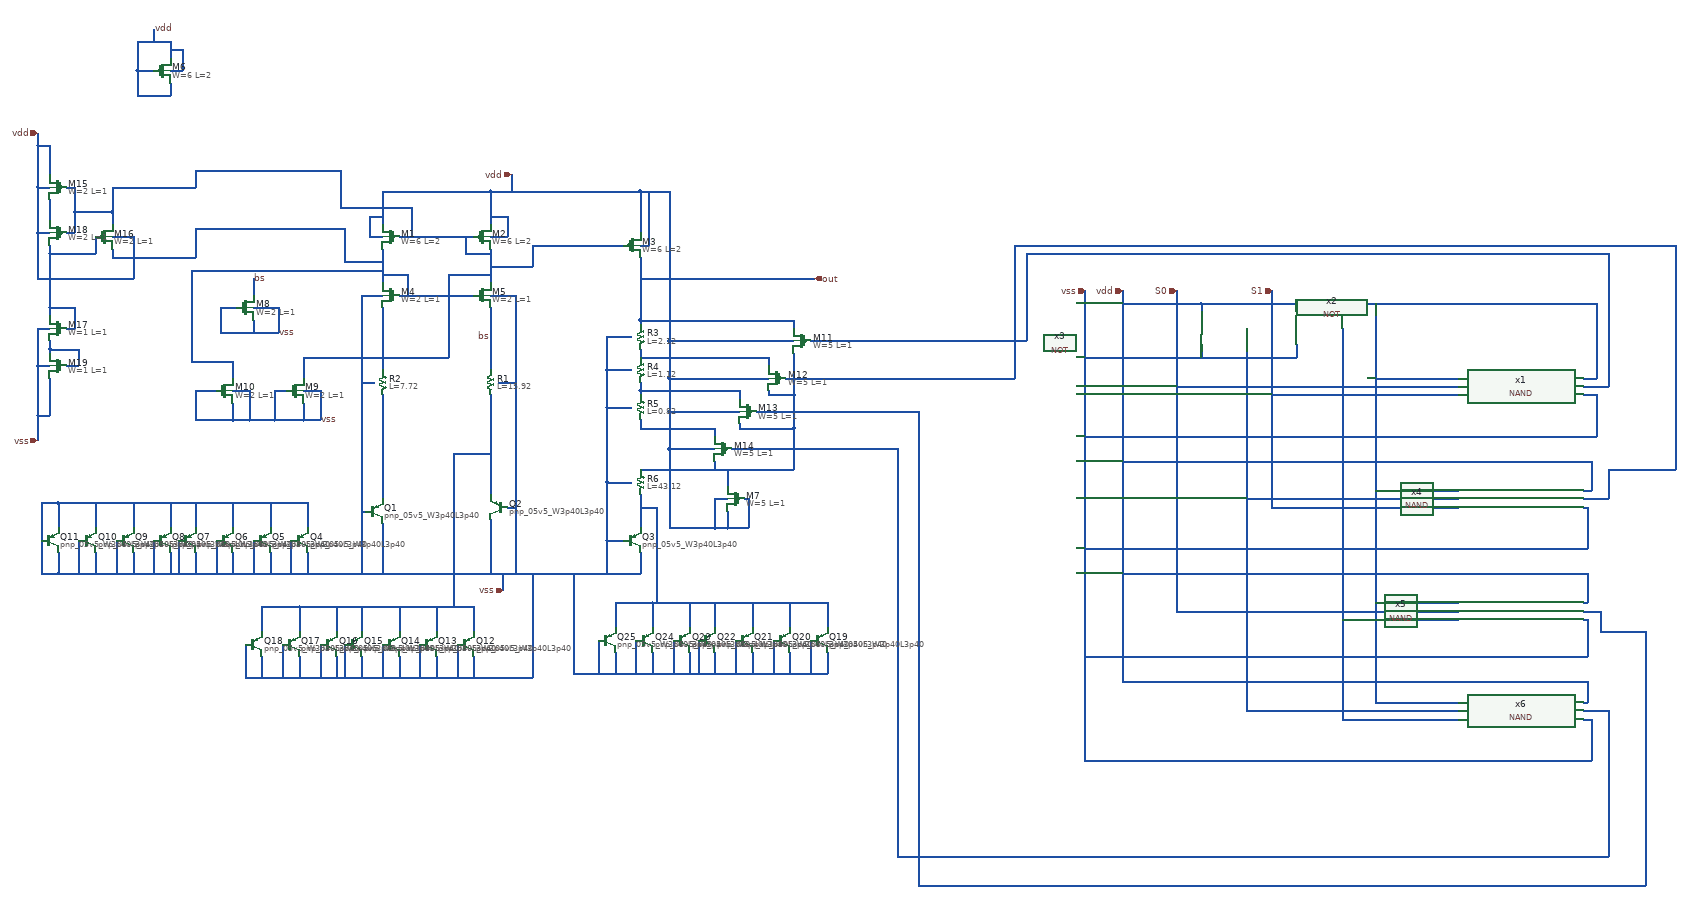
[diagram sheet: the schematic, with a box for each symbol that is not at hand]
v {xschem version=3.4.8RC file_version=1.3}
G {}
K {}
V {}
S {}
F {}
E {}
P 4 1 -840 -730 {}
N 230 -160 230 -110 {lab=#net1}
N 150 -190 210 -190 {lab=vss}
N 150 -190 150 -80 {lab=vss}
N 230 -340 230 -320 {lab=#net2}
N 150 -370 150 -190 {lab=vss}
N 150 -460 210 -460 {lab=vss}
N 150 -370 210 -370 {lab=vss}
N 230 -580 230 -570 {lab=out}
N 150 -540 210 -540 {lab=vss}
N 150 -540 150 -460 {lab=vss}
N 600 -580 600 -560 {lab=out}
N 470 -330 470 -320 {lab=#net3}
N 540 -410 540 -400 {lab=#net3}
N 510 -360 690 -360 {lab=#net4}
N 300 -360 300 -270 {lab=vdd}
N 600 -320 600 -220 {lab=#net3}
N 470 -320 600 -320 {lab=#net3}
N 580 -440 680 -440 {lab=#net5}
N 600 -500 600 -400 {lab=#net3}
N 640 -530 680 -530 {lab=#net6}
N 540 -400 600 -400 {lab=#net3}
N 230 -410 470 -410 {lab=#net7}
N 470 -410 470 -390 {lab=#net7}
N 540 -490 540 -470 {lab=#net8}
N 230 -490 540 -490 {lab=#net8}
N 300 -440 540 -440 {lab=vdd}
N 300 -530 600 -530 {lab=vdd}
N 230 -580 600 -580 {lab=out}
N 410 -320 410 -300 {lab=#net2}
N 230 -320 410 -320 {lab=#net2}
N 410 -220 600 -220 {lab=#net3}
N 410 -240 410 -220 {lab=#net3}
N 450 -270 690 -270 {lab=#net9}
N 300 -270 410 -270 {lab=vdd}
N 300 -360 470 -360 {lab=vdd}
N 230 -410 230 -400 {lab=#net7}
N 230 -510 230 -490 {lab=#net8}
N 150 -460 150 -370 {lab=vss}
N 230 -430 230 -410 {lab=#net7}
N 300 -530 300 -440 {lab=vdd}
N 600 -400 600 -320 {lab=#net3}
N 230 -220 410 -220 {lab=#net3}
N 300 -440 300 -360 {lab=vdd}
N 230 -110 230 -80 {lab=#net1}
N -390 -890 -390 -810 {lab=vdd}
N -390 -890 -130 -890 {lab=vdd}
N -130 -890 -130 -810 {lab=vdd}
N -130 -890 230 -890 {lab=vdd}
N 230 -890 230 -790 {lab=vdd}
N 230 -730 230 -580 {lab=out}
N 230 -890 270 -890 {lab=vdd}
N 230 -760 250 -760 {lab=vdd}
N 250 -890 250 -760 {lab=vdd}
N 300 -890 300 -530 {lab=vdd}
N 270 -890 300 -890 {lab=vdd}
N -390 -750 -390 -670 {lab=#net10}
N -130 -750 -130 -670 {lab=#net11}
N -130 -780 -90 -780 {lab=vdd}
N -90 -830 -90 -780 {lab=vdd}
N -130 -830 -90 -830 {lab=vdd}
N -420 -780 -390 -780 {lab=vdd}
N -420 -830 -420 -780 {lab=vdd}
N -420 -830 -390 -830 {lab=vdd}
N -350 -640 -170 -640 {lab=#net10}
N -390 -690 -330 -690 {lab=#net10}
N -330 -690 -330 -640 {lab=#net10}
N -350 -780 -170 -780 {lab=#net11}
N -190 -780 -190 -740 {lab=#net11}
N -190 -740 -130 -740 {lab=#net11}
N -130 -710 -30 -710 {lab=#net11}
N -30 -760 -30 -710 {lab=#net11}
N -30 -760 190 -760 {lab=#net11}
N -390 -610 -390 -460 {lab=#net12}
N -130 -610 -130 -460 {lab=bs}
N -390 -400 -390 -170 {lab=#net13}
N -130 -400 -130 -170 {lab=#net14}
N -390 -170 -390 -150 {lab=#net13}
N -130 -170 -130 -160 {lab=#net14}
N -130 -100 -130 30 {lab=vss}
N -130 30 230 30 {lab=vss}
N 230 -20 230 30 {lab=vss}
N 150 -50 190 -50 {lab=vss}
N 150 -80 150 -50 {lab=vss}
N -390 30 -130 30 {lab=vss}
N -390 -90 -390 30 {lab=vss}
N 150 -50 150 30 {lab=vss}
N -130 -640 -70 -640 {lab=vss}
N -70 -640 -70 30 {lab=vss}
N -110 -430 -70 -430 {lab=vss}
N -90 -130 -70 -130 {lab=vss}
N -440 -640 -390 -640 {lab=vss}
N -440 -640 -440 30 {lab=vss}
N -440 30 -390 30 {lab=vss}
N -440 -120 -430 -120 {lab=vss}
N -440 -430 -410 -430 {lab=vss}
N 230 -680 650 -680 {lab=out}
N -80 -930 -80 -890 {lab=vdd}
N -100 30 -100 70 {lab=vss}
N -320 -850 -320 -780 {lab=#net11}
N -900 -1240 -900 -1210 {lab=vdd}
N -900 -1150 -900 -1120 {lab=vdd}
N -900 -1180 -870 -1180 {lab=vdd}
N -870 -1230 -870 -1180 {lab=vdd}
N -900 -1230 -870 -1230 {lab=vdd}
N -900 -1250 -900 -1240 {lab=vdd}
N -980 -1180 -940 -1180 {lab=vdd}
N -980 -1120 -900 -1120 {lab=vdd}
N -980 -1180 -980 -1120 {lab=vdd}
N -980 -1250 -980 -1180 {lab=vdd}
N -980 -1250 -900 -1250 {lab=vdd}
N -940 -1280 -940 -1250 {lab=vdd}
N 440 -220 440 -180 {lab=#net3}
N 440 -120 440 -80 {lab=vdd}
N 440 -80 490 -80 {lab=vdd}
N 490 -150 490 -80 {lab=vdd}
N 480 -150 490 -150 {lab=vdd}
N 410 -150 440 -150 {lab=vdd}
N 410 -150 410 -110 {lab=vdd}
N 410 -110 410 -80 {lab=vdd}
N 410 -80 440 -80 {lab=vdd}
N 300 -270 300 -80 {lab=vdd}
N 300 -80 410 -80 {lab=vdd}
N -700 -680 -700 -640 {lab=bs}
N -700 -580 -700 -550 {lab=vss}
N -780 -610 -740 -610 {lab=vss}
N -700 -610 -640 -610 {lab=vss}
N -580 -490 -580 -440 {lab=#net11}
N -580 -380 -580 -340 {lab=vss}
N -650 -410 -620 -410 {lab=vss}
N -650 -410 -650 -340 {lab=vss}
N -650 -340 -580 -340 {lab=vss}
N -580 -410 -540 -410 {lab=vss}
N -540 -410 -540 -340 {lab=vss}
N -580 -340 -540 -340 {lab=vss}
N -750 -480 -750 -440 {lab=#net10}
N -750 -380 -750 -350 {lab=vss}
N -840 -410 -790 -410 {lab=vss}
N -750 -410 -710 -410 {lab=vss}
N -710 -410 -710 -350 {lab=vss}
N -710 -350 -710 -340 {lab=vss}
N -710 -340 -650 -340 {lab=vss}
N -750 -350 -750 -340 {lab=vss}
N -750 -340 -710 -340 {lab=vss}
N -840 -410 -840 -340 {lab=vss}
N -840 -340 -750 -340 {lab=vss}
N -580 -490 -230 -490 {lab=#net11}
N -230 -690 -230 -490 {lab=#net11}
N -230 -690 -130 -690 {lab=#net11}
N -820 -480 -750 -480 {lab=#net10}
N -850 -480 -820 -480 {lab=#net10}
N -850 -700 -850 -480 {lab=#net10}
N -850 -700 -390 -700 {lab=#net10}
N -1170 -140 -1170 -80 {lab=vss}
N -1170 -140 -570 -140 {lab=vss}
N -570 -140 -570 -80 {lab=vss}
N -660 -140 -660 -80 {lab=vss}
N -750 -140 -750 -80 {lab=vss}
N -840 -140 -840 -80 {lab=vss}
N -900 -140 -900 -80 {lab=vss}
N -990 -140 -990 -80 {lab=vss}
N -1080 -140 -1080 -80 {lab=vss}
N -1170 -20 -1170 30 {lab=vss}
N -1170 30 -570 30 {lab=vss}
N -570 -20 -570 30 {lab=vss}
N -660 -20 -660 30 {lab=vss}
N -750 -20 -750 30 {lab=vss}
N -840 -20 -840 30 {lab=vss}
N -900 -20 -900 30 {lab=vss}
N -990 -20 -990 30 {lab=vss}
N -1080 -20 -1080 30 {lab=vss}
N -610 -50 -610 30 {lab=vss}
N -700 -50 -700 30 {lab=vss}
N -790 -50 -790 30 {lab=vss}
N -880 -50 -880 30 {lab=vss}
N -940 -50 -940 30 {lab=vss}
N -1030 -50 -1030 30 {lab=vss}
N -1120 -50 -1120 30 {lab=vss}
N -1210 -50 -1210 30 {lab=vss}
N -1210 30 -1170 30 {lab=vss}
N -1210 -140 -1210 -50 {lab=vss}
N -1210 -140 -1170 -140 {lab=vss}
N -170 110 -170 170 {lab=#net14}
N -260 110 -260 170 {lab=#net14}
N -350 110 -350 170 {lab=#net14}
N -440 110 -440 170 {lab=#net14}
N -500 110 -500 170 {lab=#net14}
N -590 110 -590 170 {lab=#net14}
N -680 110 -680 170 {lab=#net14}
N -170 230 -170 280 {lab=vss}
N -260 230 -260 280 {lab=vss}
N -350 230 -350 280 {lab=vss}
N -440 230 -440 280 {lab=vss}
N -500 230 -500 280 {lab=vss}
N -590 230 -590 280 {lab=vss}
N -680 230 -680 280 {lab=vss}
N -210 200 -210 280 {lab=vss}
N -300 200 -300 280 {lab=vss}
N -390 200 -390 280 {lab=vss}
N -480 200 -480 280 {lab=vss}
N -540 200 -540 280 {lab=vss}
N -630 200 -630 280 {lab=vss}
N -720 200 -720 280 {lab=vss}
N -680 110 -590 110 {lab=#net14}
N -590 110 -170 110 {lab=#net14}
N -720 280 -170 280 {lab=vss}
N 680 100 680 160 {lab=#net1}
N 590 100 590 160 {lab=#net1}
N 500 100 500 160 {lab=#net1}
N 410 100 410 160 {lab=#net1}
N 350 100 350 160 {lab=#net1}
N 260 100 260 160 {lab=#net1}
N 170 100 170 160 {lab=#net1}
N 680 220 680 270 {lab=vss}
N 590 220 590 270 {lab=vss}
N 500 220 500 270 {lab=vss}
N 410 220 410 270 {lab=vss}
N 350 220 350 270 {lab=vss}
N 260 220 260 270 {lab=vss}
N 170 220 170 270 {lab=vss}
N 640 190 640 270 {lab=vss}
N 550 190 550 270 {lab=vss}
N 460 190 460 270 {lab=vss}
N 370 190 370 270 {lab=vss}
N 310 190 310 270 {lab=vss}
N 220 190 220 270 {lab=vss}
N 130 190 130 270 {lab=vss}
N 170 100 260 100 {lab=#net1}
N 260 100 680 100 {lab=#net1}
N 130 270 680 270 {lab=vss}
N -570 30 -440 30 {lab=vss}
N -220 -260 -220 110 {lab=#net14}
N -220 -260 -130 -260 {lab=#net14}
N -30 30 -30 270 {lab=vss}
N -30 270 -30 280 {lab=vss}
N -170 280 -30 280 {lab=vss}
N 230 -130 270 -130 {lab=#net1}
N 270 -130 270 100 {lab=#net1}
N 70 30 70 270 {lab=vss}
N 70 270 130 270 {lab=vss}
N -780 -610 -780 -550 {lab=vss}
N -780 -550 -700 -550 {lab=vss}
N -700 -550 -640 -550 {lab=vss}
N -640 -610 -640 -550 {lab=vss}
N -1130 -840 -1040 -840 {lab=#net11}
N -1130 -840 -1130 -790 {lab=#net11}
N -1150 -790 -1130 -790 {lab=#net11}
N -1190 -610 -1190 -590 {lab=#net15}
N -1190 -740 -1080 -740 {lab=#net15}
N -1130 -610 -1130 -560 {lab=#net15}
N -1190 -610 -1130 -610 {lab=#net15}
N -1150 -560 -1130 -560 {lab=#net15}
N -1190 -1000 -1190 -930 {lab=vdd}
N -1080 -780 -1080 -740 {lab=#net15}
N -1040 -840 -1040 -810 {lab=#net11}
N -1040 -900 -1040 -840 {lab=#net11}
N -1150 -900 -1130 -900 {lab=#net11}
N -1220 -900 -1190 -900 {lab=vdd}
N -1220 -900 -1220 -790 {lab=vdd}
N -1040 -780 -990 -780 {lab=vdd}
N -990 -780 -990 -680 {lab=vdd}
N -1220 -680 -990 -680 {lab=vdd}
N -1220 -790 -1220 -680 {lab=vdd}
N -1220 -1000 -1220 -900 {lab=vdd}
N -1220 -1000 -1190 -1000 {lab=vdd}
N -1220 -560 -1190 -560 {lab=vss}
N -1220 -1030 -1220 -1000 {lab=vdd}
N -1130 -900 -1130 -840 {lab=#net11}
N -1190 -760 -1190 -740 {lab=#net15}
N -1190 -740 -1190 -610 {lab=#net15}
N -1220 -470 -1220 -350 {lab=vss}
N -1220 -350 -1190 -350 {lab=vss}
N -1190 -870 -1190 -820 {lab=#net16}
N -1220 -790 -1190 -790 {lab=vdd}
N -1190 -440 -1190 -350 {lab=vss}
N -1190 -510 -1190 -500 {lab=#net17}
N -1220 -470 -1190 -470 {lab=vss}
N -1150 -470 -1120 -470 {lab=#net17}
N -1120 -510 -1120 -470 {lab=#net17}
N -1190 -510 -1120 -510 {lab=#net17}
N -1220 -350 -1220 -290 {lab=vss}
N -1220 -560 -1220 -470 {lab=vss}
N -1190 -530 -1190 -510 {lab=#net17}
N 1520 -650 1520 -560 {lab=S0}
N 1520 -560 1520 -160 {lab=S0}
N 1750 -650 1750 -560 {lab=S1}
N 1750 -520 1750 -130 {lab=S1}
N 1580 -620 1580 -600 {lab=vdd}
N 1580 -520 1580 -490 {lab=vss}
N 1810 -520 1810 -490 {lab=vss}
N 1690 -560 1690 -180 {lab=#net18}
N 1920 -560 1920 -180 {lab=#net19}
N 2000 -180 2000 270 {lab=vdd}
N 1920 -180 1920 270 {lab=#net19}
N 1690 -180 1690 270 {lab=#net18}
N 1690 270 1690 280 {lab=#net18}
N 1920 270 1920 280 {lab=#net19}
N 2000 270 2000 280 {lab=vdd}
N 1300 -650 1300 -190 {lab=vss}
N 1300 -190 1300 260 {lab=vss}
N 1390 -650 1390 -190 {lab=vdd}
N 1390 -190 1390 260 {lab=vdd}
N 1390 -620 1580 -620 {lab=vdd}
N 1580 -620 1810 -620 {lab=vdd}
N 1810 -620 1810 -600 {lab=vdd}
N 1300 -490 1810 -490 {lab=vss}
N 2000 -440 2200 -440 {lab=vdd}
N 2000 -170 2200 -170 {lab=vdd}
N 1810 -620 2290 -620 {lab=vdd}
N 1300 -300 2290 -300 {lab=vss}
N 1390 -240 2290 -240 {lab=vdd}
N 1300 -30 2290 -30 {lab=vss}
N 1390 30 2290 30 {lab=vdd}
N 1300 230 2290 230 {lab=vss}
N 2000 280 2000 340 {lab=vdd}
N 2000 340 2200 340 {lab=vdd}
N 1300 260 1300 480 {lab=vss}
N 1300 480 2290 480 {lab=vss}
N 1390 260 1390 280 {lab=vdd}
N 1390 290 2290 290 {lab=vdd}
N 1390 280 1390 290 {lab=vdd}
N 2000 100 2200 100 {lab=vdd}
N 1520 -420 2200 -420 {lab=S0}
N 1750 -400 2200 -400 {lab=S1}
N 1690 -150 2200 -150 {lab=#net18}
N 1750 -130 2200 -130 {lab=S1}
N 1520 120 2200 120 {lab=S0}
N 1920 140 2200 140 {lab=#net19}
N 1920 280 1920 350 {lab=#net19}
N 1690 360 2200 360 {lab=#net18}
N 1690 280 1690 360 {lab=#net18}
N 1920 380 2200 380 {lab=#net19}
N 1920 350 1920 380 {lab=#net19}
N 1750 -560 1750 -520 {lab=S1}
N 1520 -160 1520 120 {lab=S0}
N 2000 -620 2000 -180 {lab=vdd}
N 2500 -440 2530 -440 {lab=vdd}
N 2290 -620 2530 -620 {lab=vdd}
N 2530 -620 2530 -440 {lab=vdd}
N 2290 -300 2530 -300 {lab=vss}
N 2530 -400 2530 -300 {lab=vss}
N 2500 -400 2530 -400 {lab=vss}
N 2290 -240 2520 -240 {lab=vdd}
N 2520 -240 2520 -170 {lab=vdd}
N 2500 -170 2520 -170 {lab=vdd}
N 2290 -30 2510 -30 {lab=vss}
N 2510 -130 2510 -30 {lab=vss}
N 2500 -130 2510 -130 {lab=vss}
N 2290 30 2510 30 {lab=vdd}
N 2510 30 2510 100 {lab=vdd}
N 2500 100 2510 100 {lab=vdd}
N 2290 230 2510 230 {lab=vss}
N 2510 140 2510 230 {lab=vss}
N 2500 140 2510 140 {lab=vss}
N 2290 290 2500 290 {lab=vdd}
N 2500 290 2510 290 {lab=vdd}
N 2510 290 2510 340 {lab=vdd}
N 2500 340 2510 340 {lab=vdd}
N 2290 480 2520 480 {lab=vss}
N 2520 380 2520 480 {lab=vss}
N 2500 380 2520 380 {lab=vss}
N 690 -270 850 -270 {lab=#net9}
N 850 -270 850 710 {lab=#net9}
N 2560 360 2560 710 {lab=#net9}
N 850 710 2560 710 {lab=#net9}
N 690 -360 900 -360 {lab=#net4}
N 900 -360 900 780 {lab=#net4}
N 900 780 2650 780 {lab=#net4}
N 2650 170 2650 780 {lab=#net4}
N 2540 170 2650 170 {lab=#net4}
N 2540 120 2540 170 {lab=#net4}
N 680 -440 1130 -440 {lab=#net5}
N 1130 -760 1130 -440 {lab=#net5}
N 1130 -760 2720 -760 {lab=#net5}
N 2720 -760 2720 -220 {lab=#net5}
N 2560 -220 2720 -220 {lab=#net5}
N 2560 -220 2560 -150 {lab=#net5}
N 680 -530 1160 -530 {lab=#net6}
N 1160 -740 1160 -530 {lab=#net6}
N 1160 -740 2560 -740 {lab=#net6}
N 2560 -740 2560 -420 {lab=#net6}
N -840 -940 -840 -900 {lab=#net11}
N -840 -940 -490 -940 {lab=#net11}
N -490 -940 -490 -850 {lab=#net11}
N -840 -800 -840 -750 {lab=#net10}
N -840 -800 -500 -800 {lab=#net10}
N -500 -800 -480 -800 {lab=#net10}
N -480 -800 -480 -720 {lab=#net10}
N -1040 -900 -840 -900 {lab=#net11}
N -1040 -750 -1040 -730 {lab=#net10}
N -1040 -730 -840 -730 {lab=#net10}
N -840 -750 -840 -730 {lab=#net10}
N -490 -850 -320 -850 {lab=#net11}
N -480 -720 -390 -720 {lab=#net10}
N 2500 -420 2560 -420 {lab=#net6}
N 2500 -150 2560 -150 {lab=#net5}
N 2500 120 2540 120 {lab=#net4}
N 2500 360 2560 360 {lab=#net9}
C {sky130_fd_pr/pfet_01v8_lvt.sym} 620 -530 0 1 {name=M11
W=5
L=1
nf=1
mult=4
ad="expr('int((@nf + 1)/2) * @W / @nf * 0.29')"
pd="expr('2*int((@nf + 1)/2) * (@W / @nf + 0.29)')"
as="expr('int((@nf + 2)/2) * @W / @nf * 0.29')"
ps="expr('2*int((@nf + 2)/2) * (@W / @nf + 0.29)')"
nrd="expr('0.29 / @W ')" nrs="expr('0.29 / @W ')"
sa=0 sb=0 sd=0
model=pfet_01v8_lvt
spiceprefix=X
}
C {sky130_fd_pr/pfet_01v8_lvt.sym} 560 -440 0 1 {name=M12
W=5
L=1
nf=1
mult=4
ad="expr('int((@nf + 1)/2) * @W / @nf * 0.29')"
pd="expr('2*int((@nf + 1)/2) * (@W / @nf + 0.29)')"
as="expr('int((@nf + 2)/2) * @W / @nf * 0.29')"
ps="expr('2*int((@nf + 2)/2) * (@W / @nf + 0.29)')"
nrd="expr('0.29 / @W ')" nrs="expr('0.29 / @W ')"
sa=0 sb=0 sd=0
model=pfet_01v8_lvt
spiceprefix=X
}
C {sky130_fd_pr/pfet_01v8_lvt.sym} 490 -360 0 1 {name=M13
W=5
L=1
nf=1
mult=4
ad="expr('int((@nf + 1)/2) * @W / @nf * 0.29')"
pd="expr('2*int((@nf + 1)/2) * (@W / @nf + 0.29)')"
as="expr('int((@nf + 2)/2) * @W / @nf * 0.29')"
ps="expr('2*int((@nf + 2)/2) * (@W / @nf + 0.29)')"
nrd="expr('0.29 / @W ')" nrs="expr('0.29 / @W ')"
sa=0 sb=0 sd=0
model=pfet_01v8_lvt
spiceprefix=X
}
C {sky130_fd_pr/pfet_01v8_lvt.sym} 430 -270 0 1 {name=M14
W=5
L=1
nf=1
mult=9
ad="expr('int((@nf + 1)/2) * @W / @nf * 0.29')"
pd="expr('2*int((@nf + 1)/2) * (@W / @nf + 0.29)')"
as="expr('int((@nf + 2)/2) * @W / @nf * 0.29')"
ps="expr('2*int((@nf + 2)/2) * (@W / @nf + 0.29)')"
nrd="expr('0.29 / @W ')" nrs="expr('0.29 / @W ')"
sa=0 sb=0 sd=0
model=pfet_01v8_lvt
spiceprefix=X
}
C {sky130_fd_pr/res_high_po_1p41.sym} 230 -540 0 0 {name=R3
L=2.12
model=res_high_po_1p41
spiceprefix=X
mult=1}
C {sky130_fd_pr/res_high_po_1p41.sym} 230 -460 0 0 {name=R4
L=1.12
model=res_high_po_1p41
spiceprefix=X
mult=2}
C {sky130_fd_pr/res_high_po_1p41.sym} 230 -370 0 0 {name=R5
L=0.82
model=res_high_po_1p41
spiceprefix=X
mult=1}
C {sky130_fd_pr/res_high_po_1p41.sym} 230 -190 0 0 {name=R6
L=43.12
model=res_high_po_1p41
spiceprefix=X
mult=1}
C {sky130_fd_pr/pfet_01v8_lvt.sym} -370 -780 0 1 {name=M1
W=6
L=2
nf=1
mult=6
ad="expr('int((@nf + 1)/2) * @W / @nf * 0.29')"
pd="expr('2*int((@nf + 1)/2) * (@W / @nf + 0.29)')"
as="expr('int((@nf + 2)/2) * @W / @nf * 0.29')"
ps="expr('2*int((@nf + 2)/2) * (@W / @nf + 0.29)')"
nrd="expr('0.29 / @W ')" nrs="expr('0.29 / @W ')"
sa=0 sb=0 sd=0
model=pfet_01v8_lvt
spiceprefix=X
}
C {sky130_fd_pr/pfet_01v8_lvt.sym} -150 -780 0 0 {name=M2
W=6
L=2
nf=1
mult=6
ad="expr('int((@nf + 1)/2) * @W / @nf * 0.29')"
pd="expr('2*int((@nf + 1)/2) * (@W / @nf + 0.29)')"
as="expr('int((@nf + 2)/2) * @W / @nf * 0.29')"
ps="expr('2*int((@nf + 2)/2) * (@W / @nf + 0.29)')"
nrd="expr('0.29 / @W ')" nrs="expr('0.29 / @W ')"
sa=0 sb=0 sd=0
model=pfet_01v8_lvt
spiceprefix=X
}
C {sky130_fd_pr/pfet_01v8_lvt.sym} 210 -760 0 0 {name=M3
W=6
L=2
nf=1
mult=6
ad="expr('int((@nf + 1)/2) * @W / @nf * 0.29')"
pd="expr('2*int((@nf + 1)/2) * (@W / @nf + 0.29)')"
as="expr('int((@nf + 2)/2) * @W / @nf * 0.29')"
ps="expr('2*int((@nf + 2)/2) * (@W / @nf + 0.29)')"
nrd="expr('0.29 / @W ')" nrs="expr('0.29 / @W ')"
sa=0 sb=0 sd=0
model=pfet_01v8_lvt
spiceprefix=X
}
C {sky130_fd_pr/nfet_01v8_lvt.sym} -370 -640 0 1 {name=M4
W=2
L=1
nf=1
mult=8
ad="expr('int((@nf + 1)/2) * @W / @nf * 0.29')"
pd="expr('2*int((@nf + 1)/2) * (@W / @nf + 0.29)')"
as="expr('int((@nf + 2)/2) * @W / @nf * 0.29')"
ps="expr('2*int((@nf + 2)/2) * (@W / @nf + 0.29)')"
nrd="expr('0.29 / @W ')" nrs="expr('0.29 / @W ')"
sa=0 sb=0 sd=0
model=nfet_01v8_lvt
spiceprefix=X
}
C {sky130_fd_pr/nfet_01v8_lvt.sym} -150 -640 0 0 {name=M5
W=2
L=1
nf=1
mult=8
ad="expr('int((@nf + 1)/2) * @W / @nf * 0.29')"
pd="expr('2*int((@nf + 1)/2) * (@W / @nf + 0.29)')"
as="expr('int((@nf + 2)/2) * @W / @nf * 0.29')"
ps="expr('2*int((@nf + 2)/2) * (@W / @nf + 0.29)')"
nrd="expr('0.29 / @W ')" nrs="expr('0.29 / @W ')"
sa=0 sb=0 sd=0
model=nfet_01v8_lvt
spiceprefix=X
}
C {sky130_fd_pr/res_high_po_1p41.sym} -130 -430 0 1 {name=R1
L=15.92
model=res_high_po_1p41
spiceprefix=X
mult=1}
C {sky130_fd_pr/res_high_po_1p41.sym} -390 -430 0 0 {name=R2
L=7.72
model=res_high_po_1p41
spiceprefix=X
mult=1}
C {sky130_fd_pr/pnp_05v5.sym} -410 -120 0 0 {name=Q1
model=pnp_05v5_W3p40L3p40
m=1

}
C {sky130_fd_pr/pnp_05v5.sym} -110 -130 0 1 {name=Q2
model=pnp_05v5_W3p40L3p40
m=1
}
C {sky130_fd_pr/pnp_05v5.sym} 210 -50 0 0 {name=Q3
model=pnp_05v5_W3p40L3p40
m=1
}
C {iopin.sym} -80 -930 0 0 {name=p1 lab=vdd}
C {iopin.sym} -100 70 0 0 {name=p2 lab=vss}
C {opin.sym} 650 -680 0 0 {name=p6 lab=out}
C {sky130_fd_pr/pfet_01v8_lvt.sym} -920 -1180 0 0 {name=M6
W=6
L=2
nf=1
mult=6
ad="expr('int((@nf + 1)/2) * @W / @nf * 0.29')"
pd="expr('2*int((@nf + 1)/2) * (@W / @nf + 0.29)')"
as="expr('int((@nf + 2)/2) * @W / @nf * 0.29')"
ps="expr('2*int((@nf + 2)/2) * (@W / @nf + 0.29)')"
nrd="expr('0.29 / @W ')" nrs="expr('0.29 / @W ')"
sa=0 sb=0 sd=0
model=pfet_01v8_lvt
spiceprefix=X
}
C {lab_pin.sym} -940 -1280 0 1 {name=p10 sig_type=std_logic lab=vdd}
C {sky130_fd_pr/pfet_01v8_lvt.sym} 460 -150 2 0 {name=M7
W=5
L=1
nf=1
mult=1
ad="expr('int((@nf + 1)/2) * @W / @nf * 0.29')"
pd="expr('2*int((@nf + 1)/2) * (@W / @nf + 0.29)')"
as="expr('int((@nf + 2)/2) * @W / @nf * 0.29')"
ps="expr('2*int((@nf + 2)/2) * (@W / @nf + 0.29)')"
nrd="expr('0.29 / @W ')" nrs="expr('0.29 / @W ')"
sa=0 sb=0 sd=0
model=pfet_01v8_lvt
spiceprefix=X
}
C {sky130_fd_pr/nfet_01v8_lvt.sym} -720 -610 0 0 {name=M8
W=2
L=1
nf=1
mult=4
ad="expr('int((@nf + 1)/2) * @W / @nf * 0.29')"
pd="expr('2*int((@nf + 1)/2) * (@W / @nf + 0.29)')"
as="expr('int((@nf + 2)/2) * @W / @nf * 0.29')"
ps="expr('2*int((@nf + 2)/2) * (@W / @nf + 0.29)')"
nrd="expr('0.29 / @W ')" nrs="expr('0.29 / @W ')"
sa=0 sb=0 sd=0
model=nfet_01v8_lvt
spiceprefix=X
}
C {lab_pin.sym} -130 -540 0 0 {name=p11 sig_type=std_logic lab=bs}
C {lab_pin.sym} -640 -550 2 0 {name=p12 sig_type=std_logic lab=vss}
C {lab_pin.sym} -700 -680 2 0 {name=p13 sig_type=std_logic lab=bs}
C {sky130_fd_pr/nfet_01v8_lvt.sym} -600 -410 0 0 {name=M9
W=2
L=1
nf=1
mult=8
ad="expr('int((@nf + 1)/2) * @W / @nf * 0.29')"
pd="expr('2*int((@nf + 1)/2) * (@W / @nf + 0.29)')"
as="expr('int((@nf + 2)/2) * @W / @nf * 0.29')"
ps="expr('2*int((@nf + 2)/2) * (@W / @nf + 0.29)')"
nrd="expr('0.29 / @W ')" nrs="expr('0.29 / @W ')"
sa=0 sb=0 sd=0
model=nfet_01v8_lvt
spiceprefix=X
}
C {lab_pin.sym} -540 -340 2 0 {name=p16 sig_type=std_logic lab=vss}
C {sky130_fd_pr/nfet_01v8_lvt.sym} -770 -410 0 0 {name=M10
W=2
L=1
nf=1
mult=8
ad="expr('int((@nf + 1)/2) * @W / @nf * 0.29')"
pd="expr('2*int((@nf + 1)/2) * (@W / @nf + 0.29)')"
as="expr('int((@nf + 2)/2) * @W / @nf * 0.29')"
ps="expr('2*int((@nf + 2)/2) * (@W / @nf + 0.29)')"
nrd="expr('0.29 / @W ')" nrs="expr('0.29 / @W ')"
sa=0 sb=0 sd=0
model=nfet_01v8_lvt
spiceprefix=X
}
C {sky130_fd_pr/pnp_05v5.sym} -590 -50 0 0 {name=Q4
model=pnp_05v5_W3p40L3p40
m=1
}
C {sky130_fd_pr/pnp_05v5.sym} -680 -50 0 0 {name=Q5
model=pnp_05v5_W3p40L3p40
m=1

}
C {sky130_fd_pr/pnp_05v5.sym} -770 -50 0 0 {name=Q6
model=pnp_05v5_W3p40L3p40
m=1
}
C {sky130_fd_pr/pnp_05v5.sym} -860 -50 0 0 {name=Q7
model=pnp_05v5_W3p40L3p40
m=1
}
C {sky130_fd_pr/pnp_05v5.sym} -920 -50 0 0 {name=Q8
model=pnp_05v5_W3p40L3p40
m=1
}
C {sky130_fd_pr/pnp_05v5.sym} -1010 -50 0 0 {name=Q9
model=pnp_05v5_W3p40L3p40
m=1
}
C {sky130_fd_pr/pnp_05v5.sym} -1100 -50 0 0 {name=Q10
model=pnp_05v5_W3p40L3p40
m=1
}
C {sky130_fd_pr/pnp_05v5.sym} -1190 -50 0 0 {name=Q11
model=pnp_05v5_W3p40L3p40
m=1

}
C {sky130_fd_pr/pnp_05v5.sym} -190 200 0 0 {name=Q12
model=pnp_05v5_W3p40L3p40
m=1
}
C {sky130_fd_pr/pnp_05v5.sym} -280 200 0 0 {name=Q13
model=pnp_05v5_W3p40L3p40
m=1

}
C {sky130_fd_pr/pnp_05v5.sym} -370 200 0 0 {name=Q14
model=pnp_05v5_W3p40L3p40
m=1
}
C {sky130_fd_pr/pnp_05v5.sym} -460 200 0 0 {name=Q15
model=pnp_05v5_W3p40L3p40
m=1
}
C {sky130_fd_pr/pnp_05v5.sym} -520 200 0 0 {name=Q16
model=pnp_05v5_W3p40L3p40
m=1
}
C {sky130_fd_pr/pnp_05v5.sym} -610 200 0 0 {name=Q17
model=pnp_05v5_W3p40L3p40
m=1
}
C {sky130_fd_pr/pnp_05v5.sym} -700 200 0 0 {name=Q18
model=pnp_05v5_W3p40L3p40
m=1
}
C {sky130_fd_pr/pnp_05v5.sym} 660 190 0 0 {name=Q19
model=pnp_05v5_W3p40L3p40
m=1
}
C {sky130_fd_pr/pnp_05v5.sym} 570 190 0 0 {name=Q20
model=pnp_05v5_W3p40L3p40
m=1

}
C {sky130_fd_pr/pnp_05v5.sym} 480 190 0 0 {name=Q21
model=pnp_05v5_W3p40L3p40
m=1
}
C {sky130_fd_pr/pnp_05v5.sym} 390 190 0 0 {name=Q22
model=pnp_05v5_W3p40L3p40
m=1
}
C {sky130_fd_pr/pnp_05v5.sym} 330 190 0 0 {name=Q23
model=pnp_05v5_W3p40L3p40
m=1
}
C {sky130_fd_pr/pnp_05v5.sym} 240 190 0 0 {name=Q24
model=pnp_05v5_W3p40L3p40
m=1
}
C {sky130_fd_pr/pnp_05v5.sym} 150 190 0 0 {name=Q25
model=pnp_05v5_W3p40L3p40
m=1
}
C {sky130_fd_pr/pfet_01v8_lvt.sym} -1170 -900 0 1 {name=M15
W=2
L=1
nf=1
mult=1
ad="expr('int((@nf + 1)/2) * @W / @nf * 0.29')"
pd="expr('2*int((@nf + 1)/2) * (@W / @nf + 0.29)')"
as="expr('int((@nf + 2)/2) * @W / @nf * 0.29')"
ps="expr('2*int((@nf + 2)/2) * (@W / @nf + 0.29)')"
nrd="expr('0.29 / @W ')" nrs="expr('0.29 / @W ')"
sa=0 sb=0 sd=0
model=pfet_01v8_lvt
spiceprefix=X
}
C {sky130_fd_pr/pfet_01v8_lvt.sym} -1060 -780 0 0 {name=M16
W=2
L=1
nf=1
mult=2
ad="expr('int((@nf + 1)/2) * @W / @nf * 0.29')"
pd="expr('2*int((@nf + 1)/2) * (@W / @nf + 0.29)')"
as="expr('int((@nf + 2)/2) * @W / @nf * 0.29')"
ps="expr('2*int((@nf + 2)/2) * (@W / @nf + 0.29)')"
nrd="expr('0.29 / @W ')" nrs="expr('0.29 / @W ')"
sa=0 sb=0 sd=0
model=pfet_01v8_lvt
spiceprefix=X
}
C {sky130_fd_pr/nfet_01v8_lvt.sym} -1170 -560 0 1 {name=M17
W=1
L=1
nf=1
mult=1
ad="expr('int((@nf + 1)/2) * @W / @nf * 0.29')"
pd="expr('2*int((@nf + 1)/2) * (@W / @nf + 0.29)')"
as="expr('int((@nf + 2)/2) * @W / @nf * 0.29')"
ps="expr('2*int((@nf + 2)/2) * (@W / @nf + 0.29)')"
nrd="expr('0.29 / @W ')" nrs="expr('0.29 / @W ')"
sa=0 sb=0 sd=0
model=nfet_01v8_lvt
spiceprefix=X
}
C {iopin.sym} -1220 -1030 0 0 {name=p14 lab=vdd}
C {sky130_fd_pr/pfet_01v8_lvt.sym} -1170 -790 0 1 {name=M18
W=2
L=1
nf=1
mult=1
ad="expr('int((@nf + 1)/2) * @W / @nf * 0.29')"
pd="expr('2*int((@nf + 1)/2) * (@W / @nf + 0.29)')"
as="expr('int((@nf + 2)/2) * @W / @nf * 0.29')"
ps="expr('2*int((@nf + 2)/2) * (@W / @nf + 0.29)')"
nrd="expr('0.29 / @W ')" nrs="expr('0.29 / @W ')"
sa=0 sb=0 sd=0
model=pfet_01v8_lvt
spiceprefix=X
}
C {sky130_fd_pr/nfet_01v8_lvt.sym} -1170 -470 0 1 {name=M19
W=1
L=1
nf=1
mult=1
ad="expr('int((@nf + 1)/2) * @W / @nf * 0.29')"
pd="expr('2*int((@nf + 1)/2) * (@W / @nf + 0.29)')"
as="expr('int((@nf + 2)/2) * @W / @nf * 0.29')"
ps="expr('2*int((@nf + 2)/2) * (@W / @nf + 0.29)')"
nrd="expr('0.29 / @W ')" nrs="expr('0.29 / @W ')"
sa=0 sb=0 sd=0
model=nfet_01v8_lvt
spiceprefix=X
}
C {iopin.sym} -1220 -290 0 0 {name=p15 lab=vss}
C {NAND.sym} 2350 -420 0 0 {name=x1}
C {NOT.sym} 1900 -540 0 0 {name=x2}
C {NOT.sym} 1670 -540 0 0 {name=x3}
C {NAND.sym} 2350 -150 0 0 {name=x4}
C {NAND.sym} 2350 120 0 0 {name=x5}
C {NAND.sym} 2350 360 0 0 {name=x6}
C {ipin.sym} 1520 -650 0 0 {name=p19 lab=S0}
C {ipin.sym} 1750 -650 0 0 {name=p20 lab=S1}
C {iopin.sym} 1390 -650 0 0 {name=p21 lab=vdd}
C {iopin.sym} 1300 -650 0 0 {name=p22 lab=vss}
